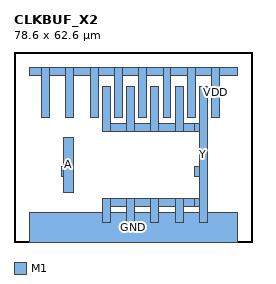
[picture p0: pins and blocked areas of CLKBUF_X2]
MACRO CLKBUF_X2
  CLASS CORE ;
  ORIGIN 0 0 ;
  SIZE 78.600 BY 62.600 ;
  SYMMETRY X Y ;
  SITE TR1um_site ;
  PIN A
    DIRECTION INPUT ;
    USE SIGNAL ;
    PORT
      LAYER M1 ;
        RECT 15.600 21.600 16.300 25.000 ;
      LAYER M1 ;
        RECT 16.300 16.400 19.700 34.400 ;
    END
  END A
  PIN Y
    DIRECTION OUTPUT ;
    USE SIGNAL ;
    PORT
      LAYER M1 ;
        RECT 29.100 6.400 31.700 14.400 ;
      LAYER M1 ;
        RECT 29.100 36.400 31.700 51.200 ;
      LAYER M1 ;
        RECT 31.700 11.800 37.100 14.400 ;
      LAYER M1 ;
        RECT 31.700 36.400 37.100 39.000 ;
      LAYER M1 ;
        RECT 37.100 6.400 39.700 14.400 ;
      LAYER M1 ;
        RECT 37.100 36.400 39.700 51.200 ;
      LAYER M1 ;
        RECT 39.700 11.800 45.100 14.400 ;
      LAYER M1 ;
        RECT 39.700 36.400 45.100 39.000 ;
      LAYER M1 ;
        RECT 45.100 6.400 47.700 14.400 ;
      LAYER M1 ;
        RECT 45.100 36.400 47.700 51.200 ;
      LAYER M1 ;
        RECT 47.700 11.800 53.100 14.400 ;
      LAYER M1 ;
        RECT 47.700 36.400 53.100 39.000 ;
      LAYER M1 ;
        RECT 53.100 6.400 55.700 14.400 ;
      LAYER M1 ;
        RECT 53.100 36.400 55.700 51.200 ;
      LAYER M1 ;
        RECT 55.700 11.800 59.600 14.400 ;
      LAYER M1 ;
        RECT 55.700 36.400 59.600 39.000 ;
      LAYER M1 ;
        RECT 59.600 11.800 61.100 14.400 ;
      LAYER M1 ;
        RECT 59.600 21.600 61.100 25.000 ;
      LAYER M1 ;
        RECT 59.600 36.400 61.100 39.000 ;
      LAYER M1 ;
        RECT 61.100 6.400 63.700 51.200 ;
    END
  END Y
  PIN VDD
    DIRECTION INOUT ;
    USE POWER ;
    PORT
      LAYER M1 ;
        RECT 5.000 55.000 9.100 57.600 ;
      LAYER M1 ;
        RECT 9.100 41.000 11.700 57.600 ;
      LAYER M1 ;
        RECT 11.700 55.000 17.100 57.600 ;
      LAYER M1 ;
        RECT 17.100 41.000 19.700 57.600 ;
      LAYER M1 ;
        RECT 19.700 55.000 25.100 57.600 ;
      LAYER M1 ;
        RECT 25.100 41.000 27.700 57.600 ;
      LAYER M1 ;
        RECT 27.700 55.000 33.100 57.600 ;
      LAYER M1 ;
        RECT 33.100 41.000 35.700 57.600 ;
      LAYER M1 ;
        RECT 35.700 55.000 41.100 57.600 ;
      LAYER M1 ;
        RECT 41.100 41.000 43.700 57.600 ;
      LAYER M1 ;
        RECT 43.700 55.000 49.100 57.600 ;
      LAYER M1 ;
        RECT 49.100 41.000 51.700 57.600 ;
      LAYER M1 ;
        RECT 51.700 55.000 57.100 57.600 ;
      LAYER M1 ;
        RECT 57.100 41.000 59.700 57.600 ;
      LAYER M1 ;
        RECT 59.700 55.000 65.100 57.600 ;
      LAYER M1 ;
        RECT 65.100 41.000 67.700 57.600 ;
      LAYER M1 ;
        RECT 67.700 55.000 73.600 57.600 ;
    END
  END VDD
  PIN GND
    DIRECTION INOUT ;
    USE GROUND ;
    PORT
      LAYER M1 ;
        RECT 5.000 0.000 73.600 9.800 ;
    END
  END GND
END CLKBUF_X2
